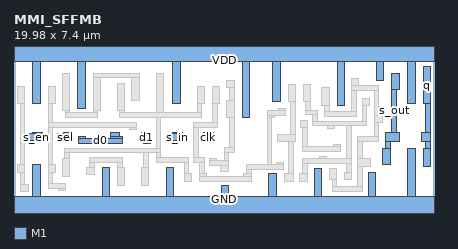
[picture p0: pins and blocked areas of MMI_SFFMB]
MACRO MMI_SFFMB
	CLASS CORE ;
	FOREIGN MMI_SFFMB 0 0 ;
	SIZE 19.98 BY 7.4 ;
	SYMMETRY X Y ;
	SITE CORE1 ;
	PIN d0
		DIRECTION input ;
		USE SIGNAL ;
		PORT
			LAYER M1 ;
			RECT 4.585 3.37 5.035 3.555 ;
			LAYER M1 ;
			RECT 3.045 3.26 3.385 3.37 ;
			LAYER M1 ;
			RECT 4.585 3.26 5.155 3.37 ;
			LAYER M1 ;
			RECT 3.045 3.03 5.155 3.26 ;
		END
		AntennaGateArea 0.4968 ;
	END d0
	PIN sel
		DIRECTION input ;
		USE SIGNAL ;
		PORT
			LAYER M1 ;
			RECT 2.365 3.5 2.815 3.555 ;
			LAYER M1 ;
			RECT 2.08 3.16 2.815 3.5 ;
			LAYER M1 ;
			RECT 2.365 3.105 2.815 3.16 ;
		END
		AntennaGateArea 0.7452 ;
	END sel
	PIN GND
		DIRECTION inout ;
		USE GROUND ;
		PORT
			LAYER M1 ;
			RECT 0.9 0.5 1.24 2.03 ;
			LAYER M1 ;
			RECT 4.19 0.5 4.53 1.88 ;
			LAYER M1 ;
			RECT 7.25 0.5 7.59 1.88 ;
			LAYER M1 ;
			RECT 9.86 0.5 10.2 1 ;
			LAYER M1 ;
			RECT 12.125 0.5 12.465 1.57 ;
			LAYER M1 ;
			RECT 14.305 0.5 14.645 1.84 ;
			LAYER M1 ;
			RECT 16.875 0.5 17.215 1.645 ;
			LAYER M1 ;
			RECT 18.74 0.5 19.08 2.765 ;
			LAYER M1 ;
			RECT 0 -0.5 19.98 0.5 ;
		END
	END GND
	PIN q
		DIRECTION output ;
		USE SIGNAL ;
		PORT
			LAYER M1 ;
			RECT 19.46 4.91 19.8 6.67 ;
			LAYER M1 ;
			RECT 19.57 3.555 19.8 4.91 ;
			LAYER M1 ;
			RECT 19.385 3.105 19.835 3.555 ;
			LAYER M1 ;
			RECT 19.57 2.765 19.8 3.105 ;
			LAYER M1 ;
			RECT 19.46 1.925 19.8 2.765 ;
		END
		AntennaDiffArea 1.3248 ;
	END q
	PIN s_in
		DIRECTION input ;
		USE SIGNAL ;
		PORT
			LAYER M1 ;
			RECT 7.545 3.485 7.995 3.555 ;
			LAYER M1 ;
			RECT 7.545 3.145 8.04 3.485 ;
			LAYER M1 ;
			RECT 7.545 3.105 7.995 3.145 ;
		END
		AntennaGateArea 0.2484 ;
	END s_in
	PIN s_en
		DIRECTION input ;
		USE SIGNAL ;
		PORT
			LAYER M1 ;
			RECT 0.885 3.5 1.335 3.555 ;
			LAYER M1 ;
			RECT 0.76 3.16 1.335 3.5 ;
			LAYER M1 ;
			RECT 0.885 3.105 1.335 3.16 ;
		END
		AntennaGateArea 1.296 ;
	END s_en
	PIN d1
		DIRECTION input ;
		USE SIGNAL ;
		PORT
			LAYER M1 ;
			RECT 6.065 3.105 6.515 3.555 ;
			LAYER M1 ;
			RECT 6.175 3.03 6.515 3.105 ;
		END
		AntennaGateArea 0.4968 ;
	END d1
	PIN VDD
		DIRECTION inout ;
		USE POWER ;
		PORT
			LAYER M1 ;
			RECT 0 6.9 19.98 7.9 ;
			LAYER M1 ;
			RECT 0.9 4.91 1.24 6.9 ;
			LAYER M1 ;
			RECT 3.04 4.705 3.38 6.9 ;
			LAYER M1 ;
			RECT 7.56 4.91 7.9 6.9 ;
			LAYER M1 ;
			RECT 10.85 4.25 11.19 6.9 ;
			LAYER M1 ;
			RECT 12.32 5 12.66 6.9 ;
			LAYER M1 ;
			RECT 15.37 4.84 15.71 6.9 ;
			LAYER M1 ;
			RECT 17.26 6 17.6 6.9 ;
			LAYER M1 ;
			RECT 18.74 4.91 19.08 6.9 ;
		END
	END VDD
	PIN s_out
		DIRECTION output ;
		USE SIGNAL ;
		PORT
			LAYER M1 ;
			RECT 17.98 5.58 18.32 6.34 ;
			LAYER M1 ;
			RECT 17.98 3.555 18.21 5.58 ;
			LAYER M1 ;
			RECT 17.66 3.105 18.355 3.555 ;
			LAYER M1 ;
			RECT 17.66 2.765 17.89 3.105 ;
			LAYER M1 ;
			RECT 17.55 2.005 17.89 2.765 ;
		END
		AntennaDiffArea 0.8568 ;
	END s_out
	PIN clk
		DIRECTION input ;
		USE CLOCK ;
		PORT
			LAYER M1 ;
			RECT 9.025 3.105 9.475 3.555 ;
		END
		AntennaGateArea 0.6408 ;
	END clk
	OBS
		LAYER M1 ;
		RECT 0.18 4.91 0.52 5.75 ;
		LAYER M1 ;
		RECT 1.62 4.91 1.96 5.75 ;
		LAYER M1 ;
		RECT 0.29 2.03 0.52 4.91 ;
		LAYER M1 ;
		RECT 1.62 4.015 1.85 4.91 ;
		LAYER M1 ;
		RECT 2.32 4.61 2.66 6.37 ;
		LAYER M1 ;
		RECT 3.76 6.14 5.95 6.37 ;
		LAYER M1 ;
		RECT 2.43 4.475 2.66 4.61 ;
		LAYER M1 ;
		RECT 3.76 4.61 4.1 6.14 ;
		LAYER M1 ;
		RECT 4.91 4.61 5.25 5.89 ;
		LAYER M1 ;
		RECT 5.61 5.09 5.95 6.14 ;
		LAYER M1 ;
		RECT 3.76 4.475 3.99 4.61 ;
		LAYER M1 ;
		RECT 2.43 4.245 3.99 4.475 ;
		LAYER M1 ;
		RECT 5.02 4.48 5.25 4.61 ;
		LAYER M1 ;
		RECT 6.76 4.48 7.1 6.37 ;
		LAYER M1 ;
		RECT 8.71 4.91 9.05 5.75 ;
		LAYER M1 ;
		RECT 9.43 4.91 9.77 5.75 ;
		LAYER M1 ;
		RECT 10.13 5.69 10.47 6.03 ;
		LAYER M1 ;
		RECT 10.24 5.09 10.47 5.69 ;
		LAYER M1 ;
		RECT 8.71 4.48 8.94 4.91 ;
		LAYER M1 ;
		RECT 5.02 4.25 8.94 4.48 ;
		LAYER M1 ;
		RECT 5.485 4.015 5.825 4.02 ;
		LAYER M1 ;
		RECT 1.62 3.785 5.825 4.015 ;
		LAYER M1 ;
		RECT 1.62 2.03 1.85 3.785 ;
		LAYER M1 ;
		RECT 5.485 3.68 5.825 3.785 ;
		LAYER M1 ;
		RECT 6.76 2.8 6.99 4.25 ;
		LAYER M1 ;
		RECT 9.43 4.015 9.66 4.91 ;
		LAYER M1 ;
		RECT 10.13 4.25 10.47 5.09 ;
		LAYER M1 ;
		RECT 13.04 5 13.38 5.84 ;
		LAYER M1 ;
		RECT 13.76 5 14.1 5.84 ;
		LAYER M1 ;
		RECT 12.56 4.59 12.9 4.7 ;
		LAYER M1 ;
		RECT 12.04 4.36 12.9 4.59 ;
		LAYER M1 ;
		RECT 12.04 4.25 12.38 4.36 ;
		LAYER M1 ;
		RECT 8.55 3.785 9.66 4.015 ;
		LAYER M1 ;
		RECT 2.425 2.57 6.99 2.8 ;
		LAYER M1 ;
		RECT 2.425 2.31 2.655 2.57 ;
		LAYER M1 ;
		RECT 0.18 1.65 0.52 2.03 ;
		LAYER M1 ;
		RECT 0.29 1.07 0.52 1.65 ;
		LAYER M1 ;
		RECT 0.29 0.73 0.67 1.07 ;
		LAYER M1 ;
		RECT 1.62 1.65 1.96 2.03 ;
		LAYER M1 ;
		RECT 1.62 1.13 1.85 1.65 ;
		LAYER M1 ;
		RECT 2.32 1.47 2.66 2.31 ;
		LAYER M1 ;
		RECT 3.58 2.11 5.14 2.34 ;
		LAYER M1 ;
		RECT 3.58 1.88 3.81 2.11 ;
		LAYER M1 ;
		RECT 4.91 1.88 5.14 2.11 ;
		LAYER M1 ;
		RECT 6.17 1.88 6.4 2.57 ;
		LAYER M1 ;
		RECT 6.76 2.34 6.99 2.57 ;
		LAYER M1 ;
		RECT 8.55 2.355 8.78 3.785 ;
		LAYER M1 ;
		RECT 10.24 2.82 10.47 4.25 ;
		LAYER M1 ;
		RECT 9.99 2.59 10.47 2.82 ;
		LAYER M1 ;
		RECT 6.76 2.11 8.32 2.34 ;
		LAYER M1 ;
		RECT 8.55 2.125 9.04 2.355 ;
		LAYER M1 ;
		RECT 3.47 1.54 3.81 1.88 ;
		LAYER M1 ;
		RECT 1.62 0.9 2.47 1.13 ;
		LAYER M1 ;
		RECT 2.13 0.79 2.47 0.9 ;
		LAYER M1 ;
		RECT 4.91 1.04 5.25 1.88 ;
		LAYER M1 ;
		RECT 6.06 1.04 6.4 1.88 ;
		LAYER M1 ;
		RECT 8.09 1.57 8.32 2.11 ;
		LAYER M1 ;
		RECT 8.81 1.57 9.04 2.125 ;
		LAYER M1 ;
		RECT 9.315 2.19 9.655 2.3 ;
		LAYER M1 ;
		RECT 9.99 2.19 10.22 2.59 ;
		LAYER M1 ;
		RECT 9.315 1.96 10.22 2.19 ;
		LAYER M1 ;
		RECT 12.04 2.03 12.27 4.25 ;
		LAYER M1 ;
		RECT 13.15 3.465 13.38 5 ;
		LAYER M1 ;
		RECT 13.87 4.61 14.1 5 ;
		LAYER M1 ;
		RECT 14.65 4.84 14.99 5.68 ;
		LAYER M1 ;
		RECT 16.04 5.765 16.38 6.1 ;
		LAYER M1 ;
		RECT 16.04 5.535 17.36 5.765 ;
		LAYER M1 ;
		RECT 13.87 4.38 14.42 4.61 ;
		LAYER M1 ;
		RECT 13.62 3.795 13.96 4.135 ;
		LAYER M1 ;
		RECT 14.19 4.085 14.42 4.38 ;
		LAYER M1 ;
		RECT 14.76 4.545 14.99 4.84 ;
		LAYER M1 ;
		RECT 16.04 4.545 16.27 5.535 ;
		LAYER M1 ;
		RECT 14.76 4.315 16.27 4.545 ;
		LAYER M1 ;
		RECT 16.56 4.84 16.9 5.18 ;
		LAYER M1 ;
		RECT 16.56 4.085 16.79 4.84 ;
		LAYER M1 ;
		RECT 14.19 3.855 16.79 4.085 ;
		LAYER M1 ;
		RECT 17.13 4.34 17.36 5.535 ;
		LAYER M1 ;
		RECT 17.13 4 17.51 4.34 ;
		LAYER M1 ;
		RECT 12.525 3.13 13.38 3.465 ;
		LAYER M1 ;
		RECT 12.525 3.125 13.3 3.13 ;
		LAYER M1 ;
		RECT 12.5 2.03 12.84 2.14 ;
		LAYER M1 ;
		RECT 9.84 1.69 10.22 1.96 ;
		LAYER M1 ;
		RECT 11.045 1.8 12.84 2.03 ;
		LAYER M1 ;
		RECT 11.045 1.57 11.275 1.8 ;
		LAYER M1 ;
		RECT 13.07 1.57 13.3 3.125 ;
		LAYER M1 ;
		RECT 13.73 2.87 13.96 3.795 ;
		LAYER M1 ;
		RECT 14.89 3.745 15.23 3.855 ;
		LAYER M1 ;
		RECT 15.215 2.87 15.555 2.98 ;
		LAYER M1 ;
		RECT 13.73 2.64 15.555 2.87 ;
		LAYER M1 ;
		RECT 14.545 2.3 14.885 2.41 ;
		LAYER M1 ;
		RECT 15.835 2.3 16.065 3.855 ;
		LAYER M1 ;
		RECT 17.13 3.36 17.36 4 ;
		LAYER M1 ;
		RECT 13.715 2.07 16.065 2.3 ;
		LAYER M1 ;
		RECT 13.715 1.57 13.945 2.07 ;
		LAYER M1 ;
		RECT 8.09 1.23 8.43 1.57 ;
		LAYER M1 ;
		RECT 8.81 1.46 9.15 1.57 ;
		LAYER M1 ;
		RECT 10.935 1.46 11.275 1.57 ;
		LAYER M1 ;
		RECT 8.81 1.23 11.275 1.46 ;
		LAYER M1 ;
		RECT 12.845 1.19 13.3 1.57 ;
		LAYER M1 ;
		RECT 13.605 1.23 13.945 1.57 ;
		LAYER M1 ;
		RECT 15.025 1.3 15.365 1.84 ;
		LAYER M1 ;
		RECT 15.835 1.645 16.065 2.07 ;
		LAYER M1 ;
		RECT 15.725 1.305 16.065 1.645 ;
		LAYER M1 ;
		RECT 16.355 3.13 17.36 3.36 ;
		LAYER M1 ;
		RECT 16.355 2.29 16.585 3.13 ;
		LAYER M1 ;
		RECT 16.355 1.95 16.975 2.29 ;
		LAYER M1 ;
		RECT 15.135 0.96 15.365 1.3 ;
		LAYER M1 ;
		RECT 16.355 0.96 16.585 1.95 ;
		LAYER M1 ;
		RECT 15.135 0.73 16.585 0.96 ;
	END
END MMI_SFFMB
